VERSION 5.7 ;
  NOWIREEXTENSIONATPIN ON ;
  DIVIDERCHAR "/" ;
  BUSBITCHARS "[]" ;
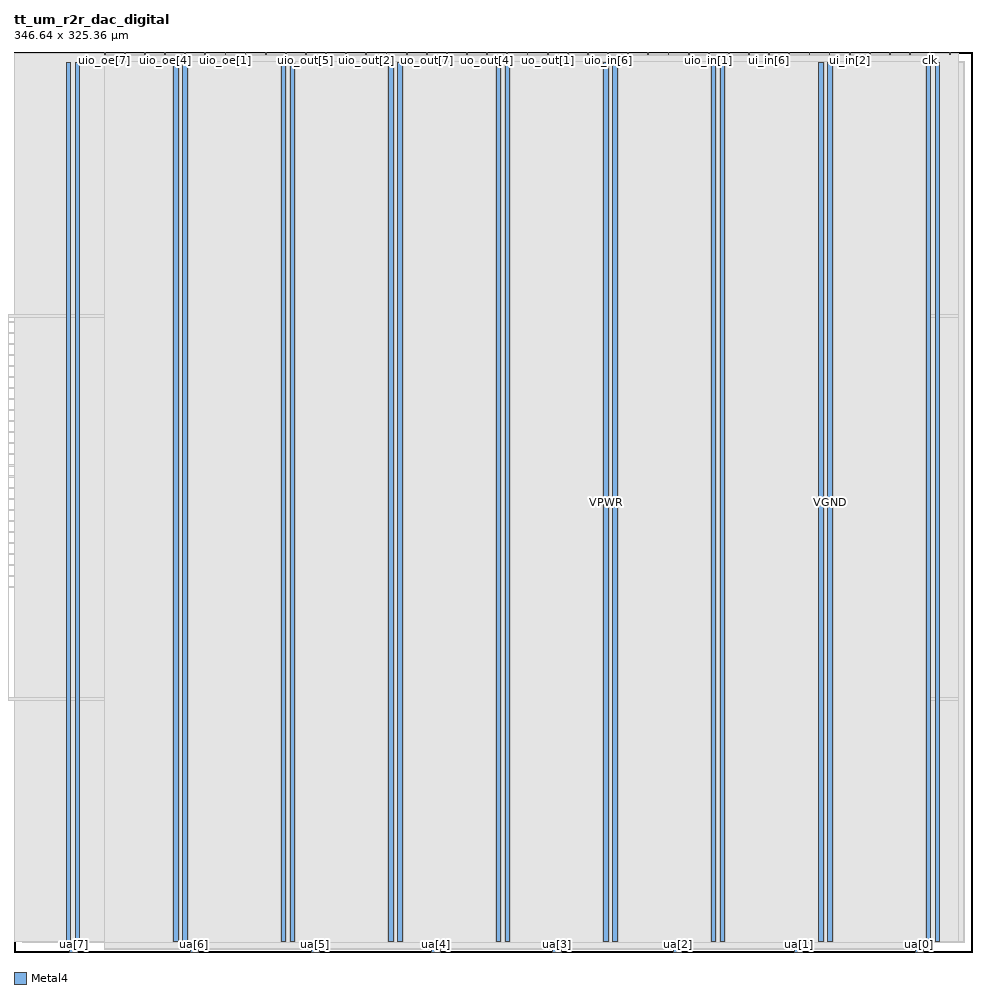
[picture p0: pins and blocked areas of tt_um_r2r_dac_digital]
MACRO tt_um_r2r_dac_digital
  CLASS BLOCK ;
  FOREIGN tt_um_r2r_dac_digital ;
  ORIGIN 0.000 0.000 ;
  SIZE 346.640 BY 325.360 ;
  PIN VGND
    DIRECTION INOUT ;
    USE GROUND ;
    PORT
      LAYER Metal4 ;
        RECT 22.180 3.620 23.780 321.740 ;
    END
    PORT
      LAYER Metal4 ;
        RECT 61.050 3.620 62.650 321.740 ;
    END
    PORT
      LAYER Metal4 ;
        RECT 99.920 3.620 101.520 321.740 ;
    END
    PORT
      LAYER Metal4 ;
        RECT 138.790 3.620 140.390 321.740 ;
    END
    PORT
      LAYER Metal4 ;
        RECT 177.660 3.620 179.260 321.740 ;
    END
    PORT
      LAYER Metal4 ;
        RECT 216.530 3.620 218.130 321.740 ;
    END
    PORT
      LAYER Metal4 ;
        RECT 255.400 3.620 257.000 321.740 ;
    END
    PORT
      LAYER Metal4 ;
        RECT 294.270 3.620 295.870 321.740 ;
    END
    PORT
      LAYER Metal4 ;
        RECT 333.140 3.620 334.740 321.740 ;
    END
  END VGND
  PIN VPWR
    DIRECTION INOUT ;
    USE POWER ;
    PORT
      LAYER Metal4 ;
        RECT 18.880 3.620 20.480 321.740 ;
    END
    PORT
      LAYER Metal4 ;
        RECT 57.750 3.620 59.350 321.740 ;
    END
    PORT
      LAYER Metal4 ;
        RECT 96.620 3.620 98.220 321.740 ;
    END
    PORT
      LAYER Metal4 ;
        RECT 135.490 3.620 137.090 321.740 ;
    END
    PORT
      LAYER Metal4 ;
        RECT 174.360 3.620 175.960 321.740 ;
    END
    PORT
      LAYER Metal4 ;
        RECT 213.230 3.620 214.830 321.740 ;
    END
    PORT
      LAYER Metal4 ;
        RECT 252.100 3.620 253.700 321.740 ;
    END
    PORT
      LAYER Metal4 ;
        RECT 290.970 3.620 292.570 321.740 ;
    END
    PORT
      LAYER Metal4 ;
        RECT 329.840 3.620 331.440 321.740 ;
    END
  END VPWR
  PIN clk
    DIRECTION INPUT ;
    USE SIGNAL ;
    ANTENNAGATEAREA 2.369000 ;
    PORT
      LAYER Metal4 ;
        RECT 331.090 324.360 331.390 325.360 ;
    END
  END clk
  PIN ena
    DIRECTION INPUT ;
    USE SIGNAL ;
    PORT
      LAYER Metal4 ;
        RECT 338.370 324.360 338.670 325.360 ;
    END
  END ena
  PIN rst_n
    DIRECTION INPUT ;
    USE SIGNAL ;
    ANTENNAGATEAREA 0.498500 ;
    PORT
      LAYER Metal4 ;
        RECT 323.810 324.360 324.110 325.360 ;
    END
  END rst_n
  PIN ua[0]
    DIRECTION INOUT ;
    USE SIGNAL ;
    PORT
      LAYER Metal4 ;
        RECT 325.820 0.000 328.820 1.000 ;
    END
  END ua[0]
  PIN ua[1]
    DIRECTION INOUT ;
    USE SIGNAL ;
    PORT
      LAYER Metal4 ;
        RECT 282.140 0.000 285.140 1.000 ;
    END
  END ua[1]
  PIN ua[2]
    DIRECTION INOUT ;
    USE SIGNAL ;
    PORT
      LAYER Metal4 ;
        RECT 238.460 0.000 241.460 1.000 ;
    END
  END ua[2]
  PIN ua[3]
    DIRECTION INOUT ;
    USE SIGNAL ;
    PORT
      LAYER Metal4 ;
        RECT 194.780 0.000 197.780 1.000 ;
    END
  END ua[3]
  PIN ua[4]
    DIRECTION INOUT ;
    USE SIGNAL ;
    PORT
      LAYER Metal4 ;
        RECT 151.100 0.000 154.100 1.000 ;
    END
  END ua[4]
  PIN ua[5]
    DIRECTION INOUT ;
    USE SIGNAL ;
    PORT
      LAYER Metal4 ;
        RECT 107.420 0.000 110.420 1.000 ;
    END
  END ua[5]
  PIN ua[6]
    DIRECTION INOUT ;
    USE SIGNAL ;
    PORT
      LAYER Metal4 ;
        RECT 63.740 0.000 66.740 1.000 ;
    END
  END ua[6]
  PIN ua[7]
    DIRECTION INOUT ;
    USE SIGNAL ;
    PORT
      LAYER Metal4 ;
        RECT 20.060 0.000 23.060 1.000 ;
    END
  END ua[7]
  PIN ui_in[0]
    DIRECTION INPUT ;
    USE SIGNAL ;
    ANTENNAGATEAREA 0.498500 ;
    PORT
      LAYER Metal4 ;
        RECT 316.530 324.360 316.830 325.360 ;
    END
  END ui_in[0]
  PIN ui_in[1]
    DIRECTION INPUT ;
    USE SIGNAL ;
    ANTENNAGATEAREA 0.498500 ;
    PORT
      LAYER Metal4 ;
        RECT 309.250 324.360 309.550 325.360 ;
    END
  END ui_in[1]
  PIN ui_in[2]
    DIRECTION INPUT ;
    USE SIGNAL ;
    ANTENNAGATEAREA 0.498500 ;
    PORT
      LAYER Metal4 ;
        RECT 301.970 324.360 302.270 325.360 ;
    END
  END ui_in[2]
  PIN ui_in[3]
    DIRECTION INPUT ;
    USE SIGNAL ;
    ANTENNAGATEAREA 0.498500 ;
    PORT
      LAYER Metal4 ;
        RECT 294.690 324.360 294.990 325.360 ;
    END
  END ui_in[3]
  PIN ui_in[4]
    DIRECTION INPUT ;
    USE SIGNAL ;
    ANTENNAGATEAREA 0.498500 ;
    PORT
      LAYER Metal4 ;
        RECT 287.410 324.360 287.710 325.360 ;
    END
  END ui_in[4]
  PIN ui_in[5]
    DIRECTION INPUT ;
    USE SIGNAL ;
    ANTENNAGATEAREA 0.498500 ;
    PORT
      LAYER Metal4 ;
        RECT 280.130 324.360 280.430 325.360 ;
    END
  END ui_in[5]
  PIN ui_in[6]
    DIRECTION INPUT ;
    USE SIGNAL ;
    ANTENNAGATEAREA 0.498500 ;
    PORT
      LAYER Metal4 ;
        RECT 272.850 324.360 273.150 325.360 ;
    END
  END ui_in[6]
  PIN ui_in[7]
    DIRECTION INPUT ;
    USE SIGNAL ;
    ANTENNAGATEAREA 0.498500 ;
    PORT
      LAYER Metal4 ;
        RECT 265.570 324.360 265.870 325.360 ;
    END
  END ui_in[7]
  PIN uio_in[0]
    DIRECTION INPUT ;
    USE SIGNAL ;
    ANTENNAGATEAREA 0.498500 ;
    PORT
      LAYER Metal4 ;
        RECT 258.290 324.360 258.590 325.360 ;
    END
  END uio_in[0]
  PIN uio_in[1]
    DIRECTION INPUT ;
    USE SIGNAL ;
    ANTENNAGATEAREA 0.498500 ;
    PORT
      LAYER Metal4 ;
        RECT 251.010 324.360 251.310 325.360 ;
    END
  END uio_in[1]
  PIN uio_in[2]
    DIRECTION INPUT ;
    USE SIGNAL ;
    ANTENNAGATEAREA 2.204000 ;
    PORT
      LAYER Metal4 ;
        RECT 243.730 324.360 244.030 325.360 ;
    END
  END uio_in[2]
  PIN uio_in[3]
    DIRECTION INPUT ;
    USE SIGNAL ;
    PORT
      LAYER Metal4 ;
        RECT 236.450 324.360 236.750 325.360 ;
    END
  END uio_in[3]
  PIN uio_in[4]
    DIRECTION INPUT ;
    USE SIGNAL ;
    PORT
      LAYER Metal4 ;
        RECT 229.170 324.360 229.470 325.360 ;
    END
  END uio_in[4]
  PIN uio_in[5]
    DIRECTION INPUT ;
    USE SIGNAL ;
    PORT
      LAYER Metal4 ;
        RECT 221.890 324.360 222.190 325.360 ;
    END
  END uio_in[5]
  PIN uio_in[6]
    DIRECTION INPUT ;
    USE SIGNAL ;
    PORT
      LAYER Metal4 ;
        RECT 214.610 324.360 214.910 325.360 ;
    END
  END uio_in[6]
  PIN uio_in[7]
    DIRECTION INPUT ;
    USE SIGNAL ;
    PORT
      LAYER Metal4 ;
        RECT 207.330 324.360 207.630 325.360 ;
    END
  END uio_in[7]
  PIN uio_oe[0]
    DIRECTION OUTPUT ;
    USE SIGNAL ;
    ANTENNADIFFAREA 0.360800 ;
    PORT
      LAYER Metal4 ;
        RECT 83.570 324.360 83.870 325.360 ;
    END
  END uio_oe[0]
  PIN uio_oe[1]
    DIRECTION OUTPUT ;
    USE SIGNAL ;
    ANTENNADIFFAREA 0.360800 ;
    PORT
      LAYER Metal4 ;
        RECT 76.290 324.360 76.590 325.360 ;
    END
  END uio_oe[1]
  PIN uio_oe[2]
    DIRECTION OUTPUT ;
    USE SIGNAL ;
    ANTENNADIFFAREA 0.360800 ;
    PORT
      LAYER Metal4 ;
        RECT 69.010 324.360 69.310 325.360 ;
    END
  END uio_oe[2]
  PIN uio_oe[3]
    DIRECTION OUTPUT ;
    USE SIGNAL ;
    ANTENNADIFFAREA 0.360800 ;
    PORT
      LAYER Metal4 ;
        RECT 61.730 324.360 62.030 325.360 ;
    END
  END uio_oe[3]
  PIN uio_oe[4]
    DIRECTION OUTPUT ;
    USE SIGNAL ;
    ANTENNADIFFAREA 0.360800 ;
    PORT
      LAYER Metal4 ;
        RECT 54.450 324.360 54.750 325.360 ;
    END
  END uio_oe[4]
  PIN uio_oe[5]
    DIRECTION OUTPUT ;
    USE SIGNAL ;
    ANTENNADIFFAREA 0.360800 ;
    PORT
      LAYER Metal4 ;
        RECT 47.170 324.360 47.470 325.360 ;
    END
  END uio_oe[5]
  PIN uio_oe[6]
    DIRECTION OUTPUT ;
    USE SIGNAL ;
    ANTENNADIFFAREA 0.360800 ;
    PORT
      LAYER Metal4 ;
        RECT 39.890 324.360 40.190 325.360 ;
    END
  END uio_oe[6]
  PIN uio_oe[7]
    DIRECTION OUTPUT ;
    USE SIGNAL ;
    ANTENNADIFFAREA 0.360800 ;
    PORT
      LAYER Metal4 ;
        RECT 32.610 324.360 32.910 325.360 ;
    END
  END uio_oe[7]
  PIN uio_out[0]
    DIRECTION OUTPUT ;
    USE SIGNAL ;
    ANTENNADIFFAREA 0.360800 ;
    PORT
      LAYER Metal4 ;
        RECT 141.810 324.360 142.110 325.360 ;
    END
  END uio_out[0]
  PIN uio_out[1]
    DIRECTION OUTPUT ;
    USE SIGNAL ;
    ANTENNADIFFAREA 0.360800 ;
    PORT
      LAYER Metal4 ;
        RECT 134.530 324.360 134.830 325.360 ;
    END
  END uio_out[1]
  PIN uio_out[2]
    DIRECTION OUTPUT ;
    USE SIGNAL ;
    ANTENNADIFFAREA 0.360800 ;
    PORT
      LAYER Metal4 ;
        RECT 127.250 324.360 127.550 325.360 ;
    END
  END uio_out[2]
  PIN uio_out[3]
    DIRECTION OUTPUT ;
    USE SIGNAL ;
    ANTENNADIFFAREA 0.360800 ;
    PORT
      LAYER Metal4 ;
        RECT 119.970 324.360 120.270 325.360 ;
    END
  END uio_out[3]
  PIN uio_out[4]
    DIRECTION OUTPUT ;
    USE SIGNAL ;
    ANTENNADIFFAREA 0.360800 ;
    PORT
      LAYER Metal4 ;
        RECT 112.690 324.360 112.990 325.360 ;
    END
  END uio_out[4]
  PIN uio_out[5]
    DIRECTION OUTPUT ;
    USE SIGNAL ;
    ANTENNADIFFAREA 0.360800 ;
    PORT
      LAYER Metal4 ;
        RECT 105.410 324.360 105.710 325.360 ;
    END
  END uio_out[5]
  PIN uio_out[6]
    DIRECTION OUTPUT ;
    USE SIGNAL ;
    ANTENNADIFFAREA 0.360800 ;
    PORT
      LAYER Metal4 ;
        RECT 98.130 324.360 98.430 325.360 ;
    END
  END uio_out[6]
  PIN uio_out[7]
    DIRECTION OUTPUT ;
    USE SIGNAL ;
    ANTENNADIFFAREA 0.360800 ;
    PORT
      LAYER Metal4 ;
        RECT 90.850 324.360 91.150 325.360 ;
    END
  END uio_out[7]
  PIN uo_out[0]
    DIRECTION OUTPUT ;
    USE SIGNAL ;
    ANTENNADIFFAREA 1.060800 ;
    PORT
      LAYER Metal4 ;
        RECT 200.050 324.360 200.350 325.360 ;
    END
  END uo_out[0]
  PIN uo_out[1]
    DIRECTION OUTPUT ;
    USE SIGNAL ;
    ANTENNADIFFAREA 1.060800 ;
    PORT
      LAYER Metal4 ;
        RECT 192.770 324.360 193.070 325.360 ;
    END
  END uo_out[1]
  PIN uo_out[2]
    DIRECTION OUTPUT ;
    USE SIGNAL ;
    ANTENNADIFFAREA 1.060800 ;
    PORT
      LAYER Metal4 ;
        RECT 185.490 324.360 185.790 325.360 ;
    END
  END uo_out[2]
  PIN uo_out[3]
    DIRECTION OUTPUT ;
    USE SIGNAL ;
    ANTENNADIFFAREA 1.060800 ;
    PORT
      LAYER Metal4 ;
        RECT 178.210 324.360 178.510 325.360 ;
    END
  END uo_out[3]
  PIN uo_out[4]
    DIRECTION OUTPUT ;
    USE SIGNAL ;
    ANTENNADIFFAREA 1.060800 ;
    PORT
      LAYER Metal4 ;
        RECT 170.930 324.360 171.230 325.360 ;
    END
  END uo_out[4]
  PIN uo_out[5]
    DIRECTION OUTPUT ;
    USE SIGNAL ;
    ANTENNADIFFAREA 1.060800 ;
    PORT
      LAYER Metal4 ;
        RECT 163.650 324.360 163.950 325.360 ;
    END
  END uo_out[5]
  PIN uo_out[6]
    DIRECTION OUTPUT ;
    USE SIGNAL ;
    ANTENNADIFFAREA 2.604400 ;
    PORT
      LAYER Metal4 ;
        RECT 156.370 324.360 156.670 325.360 ;
    END
  END uo_out[6]
  PIN uo_out[7]
    DIRECTION OUTPUT ;
    USE SIGNAL ;
    ANTENNADIFFAREA 2.604400 ;
    PORT
      LAYER Metal4 ;
        RECT 149.090 324.360 149.390 325.360 ;
    END
  END uo_out[7]
  OBS
      LAYER Nwell ;
        RECT 2.930 3.490 343.710 321.870 ;
      LAYER Metal1 ;
        RECT -99.090 91.280 -98.710 230.440 ;
        RECT -97.720 228.090 -97.340 228.140 ;
        RECT -97.730 227.690 -97.330 228.090 ;
        RECT -97.720 226.740 -97.340 227.690 ;
        RECT -97.720 224.090 -97.340 224.140 ;
        RECT -97.730 223.690 -97.330 224.090 ;
        RECT -97.720 222.740 -97.340 223.690 ;
        RECT -97.720 220.090 -97.340 220.140 ;
        RECT -97.730 219.690 -97.330 220.090 ;
        RECT -97.720 218.740 -97.340 219.690 ;
        RECT -97.720 216.090 -97.340 216.140 ;
        RECT -97.730 215.690 -97.330 216.090 ;
        RECT -97.720 214.740 -97.340 215.690 ;
        RECT -97.720 212.090 -97.340 212.140 ;
        RECT -97.730 211.690 -97.330 212.090 ;
        RECT -97.720 210.740 -97.340 211.690 ;
        RECT -97.720 208.090 -97.340 208.140 ;
        RECT -97.730 207.690 -97.330 208.090 ;
        RECT -97.720 206.740 -97.340 207.690 ;
        RECT -97.720 204.090 -97.340 204.140 ;
        RECT -97.730 203.690 -97.330 204.090 ;
        RECT -97.720 202.740 -97.340 203.690 ;
        RECT -97.720 200.090 -97.340 200.140 ;
        RECT -97.730 199.690 -97.330 200.090 ;
        RECT -97.720 198.740 -97.340 199.690 ;
        RECT -97.720 196.090 -97.340 196.140 ;
        RECT -97.730 195.690 -97.330 196.090 ;
        RECT -97.720 194.740 -97.340 195.690 ;
        RECT -97.720 192.090 -97.340 192.140 ;
        RECT -97.730 191.690 -97.330 192.090 ;
        RECT -97.720 190.740 -97.340 191.690 ;
        RECT -97.720 188.090 -97.340 188.140 ;
        RECT -97.730 187.690 -97.330 188.090 ;
        RECT -97.720 186.740 -97.340 187.690 ;
        RECT -97.720 184.090 -97.340 184.140 ;
        RECT -97.730 183.690 -97.330 184.090 ;
        RECT -97.720 182.740 -97.340 183.690 ;
        RECT -97.720 180.090 -97.340 180.140 ;
        RECT -97.730 179.690 -97.330 180.090 ;
        RECT -97.720 178.740 -97.340 179.690 ;
        RECT -97.720 176.090 -97.340 176.140 ;
        RECT -97.730 175.690 -97.330 176.090 ;
        RECT -97.720 174.740 -97.340 175.690 ;
        RECT -97.720 172.090 -97.340 172.140 ;
        RECT -97.730 171.690 -97.330 172.090 ;
        RECT -97.720 170.740 -97.340 171.690 ;
        RECT -97.720 168.090 -97.340 168.140 ;
        RECT -97.730 167.690 -97.330 168.090 ;
        RECT -97.720 166.740 -97.340 167.690 ;
        RECT -97.720 164.090 -97.340 164.140 ;
        RECT -97.730 163.690 -97.330 164.090 ;
        RECT -97.720 162.740 -97.340 163.690 ;
        RECT -97.720 160.090 -97.340 160.140 ;
        RECT -97.730 159.690 -97.330 160.090 ;
        RECT -97.720 158.740 -97.340 159.690 ;
        RECT -97.720 156.090 -97.340 156.140 ;
        RECT -97.730 155.690 -97.330 156.090 ;
        RECT -97.720 154.740 -97.340 155.690 ;
        RECT -97.720 152.090 -97.340 152.140 ;
        RECT -97.730 151.690 -97.330 152.090 ;
        RECT -97.720 150.740 -97.340 151.690 ;
        RECT -97.720 148.090 -97.340 148.140 ;
        RECT -97.730 147.690 -97.330 148.090 ;
        RECT -97.720 146.740 -97.340 147.690 ;
        RECT -97.720 144.090 -97.340 144.140 ;
        RECT -97.730 143.690 -97.330 144.090 ;
        RECT -97.720 142.740 -97.340 143.690 ;
        RECT -97.720 140.090 -97.340 140.140 ;
        RECT -97.730 139.690 -97.330 140.090 ;
        RECT -97.720 138.740 -97.340 139.690 ;
        RECT -97.720 136.090 -97.340 136.140 ;
        RECT -97.730 135.690 -97.330 136.090 ;
        RECT -97.720 134.740 -97.340 135.690 ;
        RECT -97.720 132.090 -97.340 132.140 ;
        RECT -97.730 131.690 -97.330 132.090 ;
        RECT -97.720 130.740 -97.340 131.690 ;
        RECT -99.100 90.880 -98.700 91.280 ;
        RECT 0.000 3.620 343.280 321.740 ;
      LAYER Metal2 ;
        RECT 0.000 228.090 341.460 324.710 ;
        RECT -97.730 227.690 341.460 228.090 ;
        RECT 0.000 224.090 341.460 227.690 ;
        RECT -97.730 223.690 341.460 224.090 ;
        RECT 0.000 220.090 341.460 223.690 ;
        RECT -97.730 219.690 341.460 220.090 ;
        RECT 0.000 216.090 341.460 219.690 ;
        RECT -97.730 215.690 341.460 216.090 ;
        RECT 0.000 212.090 341.460 215.690 ;
        RECT -97.730 211.690 341.460 212.090 ;
        RECT 0.000 208.090 341.460 211.690 ;
        RECT -97.730 207.690 341.460 208.090 ;
        RECT 0.000 204.090 341.460 207.690 ;
        RECT -97.730 203.690 341.460 204.090 ;
        RECT 0.000 200.090 341.460 203.690 ;
        RECT -97.730 199.690 341.460 200.090 ;
        RECT 0.000 196.090 341.460 199.690 ;
        RECT -97.730 195.690 341.460 196.090 ;
        RECT 0.000 192.090 341.460 195.690 ;
        RECT -97.730 191.690 341.460 192.090 ;
        RECT 0.000 188.090 341.460 191.690 ;
        RECT -97.730 187.690 341.460 188.090 ;
        RECT 0.000 184.090 341.460 187.690 ;
        RECT -97.730 183.690 341.460 184.090 ;
        RECT 0.000 180.090 341.460 183.690 ;
        RECT -97.730 179.690 341.460 180.090 ;
        RECT 0.000 176.090 341.460 179.690 ;
        RECT -97.730 175.690 341.460 176.090 ;
        RECT 0.000 172.090 341.460 175.690 ;
        RECT -97.730 171.690 341.460 172.090 ;
        RECT 0.000 168.090 341.460 171.690 ;
        RECT -97.730 167.690 341.460 168.090 ;
        RECT 0.000 164.090 341.460 167.690 ;
        RECT -97.730 163.690 341.460 164.090 ;
        RECT 0.000 160.090 341.460 163.690 ;
        RECT -97.730 159.690 341.460 160.090 ;
        RECT 0.000 156.090 341.460 159.690 ;
        RECT -97.730 155.690 341.460 156.090 ;
        RECT 0.000 152.090 341.460 155.690 ;
        RECT -97.730 151.690 341.460 152.090 ;
        RECT 0.000 148.090 341.460 151.690 ;
        RECT -97.730 147.690 341.460 148.090 ;
        RECT 0.000 144.090 341.460 147.690 ;
        RECT -97.730 143.690 341.460 144.090 ;
        RECT 0.000 140.090 341.460 143.690 ;
        RECT -97.730 139.690 341.460 140.090 ;
        RECT 0.000 136.090 341.460 139.690 ;
        RECT -97.730 135.690 341.460 136.090 ;
        RECT 0.000 132.090 341.460 135.690 ;
        RECT -97.730 131.690 341.460 132.090 ;
        RECT 0.000 91.280 341.460 131.690 ;
        RECT -99.100 90.880 341.460 91.280 ;
        RECT 0.000 3.730 341.460 90.880 ;
      LAYER Metal3 ;
        RECT 0.000 230.440 341.510 324.660 ;
        RECT -99.240 229.440 341.510 230.440 ;
        RECT 0.000 91.880 341.510 229.440 ;
        RECT -99.240 90.880 341.510 91.880 ;
        RECT 0.000 3.780 341.510 90.880 ;
      LAYER Metal4 ;
        RECT 33.210 324.060 39.590 324.360 ;
        RECT 40.490 324.060 46.870 324.360 ;
        RECT 47.770 324.060 54.150 324.360 ;
        RECT 55.050 324.060 61.430 324.360 ;
        RECT 62.330 324.060 68.710 324.360 ;
        RECT 69.610 324.060 75.990 324.360 ;
        RECT 76.890 324.060 83.270 324.360 ;
        RECT 84.170 324.060 90.550 324.360 ;
        RECT 91.450 324.060 97.830 324.360 ;
        RECT 98.730 324.060 105.110 324.360 ;
        RECT 106.010 324.060 112.390 324.360 ;
        RECT 113.290 324.060 119.670 324.360 ;
        RECT 120.570 324.060 126.950 324.360 ;
        RECT 127.850 324.060 134.230 324.360 ;
        RECT 135.130 324.060 141.510 324.360 ;
        RECT 142.410 324.060 148.790 324.360 ;
        RECT 149.690 324.060 156.070 324.360 ;
        RECT 156.970 324.060 163.350 324.360 ;
        RECT 164.250 324.060 170.630 324.360 ;
        RECT 171.530 324.060 177.910 324.360 ;
        RECT 178.810 324.060 185.190 324.360 ;
        RECT 186.090 324.060 192.470 324.360 ;
        RECT 193.370 324.060 199.750 324.360 ;
        RECT 200.650 324.060 207.030 324.360 ;
        RECT 207.930 324.060 214.310 324.360 ;
        RECT 215.210 324.060 221.590 324.360 ;
        RECT 222.490 324.060 228.870 324.360 ;
        RECT 229.770 324.060 236.150 324.360 ;
        RECT 237.050 324.060 243.430 324.360 ;
        RECT 244.330 324.060 250.710 324.360 ;
        RECT 251.610 324.060 257.990 324.360 ;
        RECT 258.890 324.060 265.270 324.360 ;
        RECT 266.170 324.060 272.550 324.360 ;
        RECT 273.450 324.060 279.830 324.360 ;
        RECT 280.730 324.060 287.110 324.360 ;
        RECT 288.010 324.060 294.390 324.360 ;
        RECT 295.290 324.060 301.670 324.360 ;
        RECT 302.570 324.060 308.950 324.360 ;
        RECT 309.850 324.060 316.230 324.360 ;
        RECT 317.130 324.060 323.510 324.360 ;
        RECT 324.410 324.060 330.790 324.360 ;
        RECT 32.620 322.040 331.380 324.060 ;
        RECT 32.620 3.320 57.450 322.040 ;
        RECT 59.650 3.320 60.750 322.040 ;
        RECT 62.950 3.320 96.320 322.040 ;
        RECT 98.520 3.320 99.620 322.040 ;
        RECT 101.820 3.320 135.190 322.040 ;
        RECT 137.390 3.320 138.490 322.040 ;
        RECT 140.690 3.320 174.060 322.040 ;
        RECT 176.260 3.320 177.360 322.040 ;
        RECT 179.560 3.320 212.930 322.040 ;
        RECT 215.130 3.320 216.230 322.040 ;
        RECT 218.430 3.320 251.800 322.040 ;
        RECT 254.000 3.320 255.100 322.040 ;
        RECT 257.300 3.320 290.670 322.040 ;
        RECT 292.870 3.320 293.970 322.040 ;
        RECT 296.170 3.320 329.540 322.040 ;
        RECT 32.620 1.300 331.380 3.320 ;
        RECT 32.620 1.000 63.440 1.300 ;
        RECT 67.040 1.000 107.120 1.300 ;
        RECT 110.720 1.000 150.800 1.300 ;
        RECT 154.400 1.000 194.480 1.300 ;
        RECT 198.080 1.000 238.160 1.300 ;
        RECT 241.760 1.000 281.840 1.300 ;
        RECT 285.440 1.000 325.520 1.300 ;
        RECT 329.120 1.000 331.380 1.300 ;
  END
END tt_um_r2r_dac_digital
END LIBRARY

